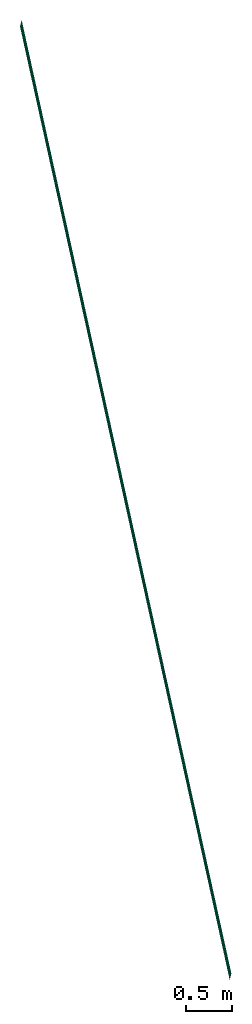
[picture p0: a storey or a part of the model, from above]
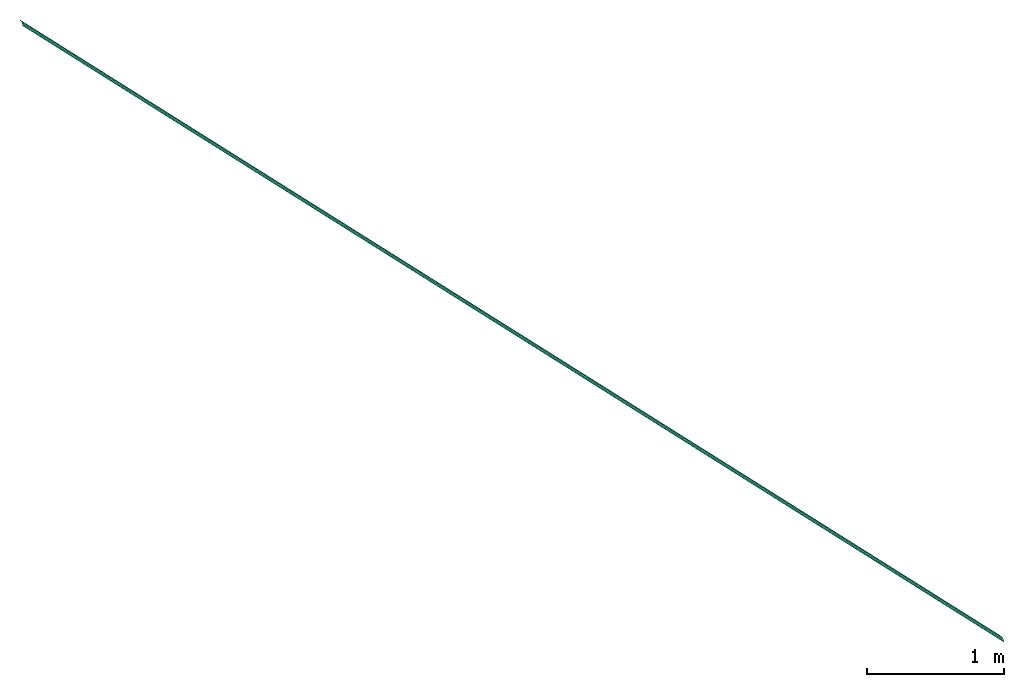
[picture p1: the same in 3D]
Properties of the parts of a building model (IFC2X3), part 1 of 2

# File
Description: ViewDefinition [CoordinationView_V2.0, QuantityTakeOffAddOnView]
File name: zv001-a-200-1-0003.ifc (Edited by Naviate Simple BIM 2022 version 6)
Time: 2026-01-09T13:08:05+01:00
Written by: ODA SDAI 24.12
Made in: Autodesk Revit 25.4.30.30 (ENU) - IFC 25.4.0.27

# IfcProject, 10001574
LongName: ENZV Kommersielt areal innland (KAI); Phase: Hovedprosjekt: 01.12.2018

# IfcSite (5)
RefElevation: 0 mm
Name | RefLatitude | RefLongitude
ENZV | 59, 54, 57, 601318 | 10, 44, 59, 999999 | Identity Data - Inventarnr.: ZV001; Building Name: ZV001; CQIncludeDoorSwing: no; CQIncludeRoomNumber: no; CQIncludeRoomNumberWindows: no; CQIncludeWindowSwing: no; Workset: Project Info; Organization Description: BIM 360://Avinor - Stavanger lufthavn/ENZV_ARK_bygg A.rvt; Prosjekt: Stavanger lufthavn, Sola; Text - 02_IfcSite: STAVANGER LUFTHAVN; 01_Modellfil: zv001-a-200-1-0003.rvt; Prosjektleder: Livar Husveg; Tiltaket gjelder: Kommersielt areal innland, KAI; Other - Project Number: 10001574; CQDoorSwingCodes: Left=V;Right=H;notMirrored =L;mirrored =R; Project Issue Date: Tilbudsprosjekt: 22.07.2018; CQWindowSwingCodes: Left=Rettv.;Right=Speilv.; Category: Project Information; Project Address: Enter address here; CQPhaseFilter: Existing:True;New Construction:True;Fase 2.0:True;Fase 3.0:True;Fase 3.9:True;Fase 4.0:True;Fase 5.1:True;Fase 5.2:True;Fase 5.3:True;Fase 5.4:True;Fase 5.9:True;Fase 5.10:True;Fase plot tegninger:True;Fase 6.0:True;; CQIncludeTemporaryDoors: no; Project Name: ENZV Kommersielt areal innland (KAI); Project Status: Hovedprosjekt: 01.12.2018; Tiltakshavers navn: Livar Husveg
Default | 42, 24, 53, 508911 | -71, -15, -29, -58837 | Pset_ProductRequirements - Category: Project Information
2 x ENZV | 58, 58, 11, 908264 | 5, 43, 59, 185523
 | 58, 58, 11, 908264 | 5, 43, 59, 185523

# IfcBuilding (5)
Name
ZV001 | LongName: ZV001; Pset_BuildingCommon - NumberOfStoreys: 8; Identity Data - Inventarnr.: ZV001; Building Name: ZV001; CQIncludeDoorSwing: no; CQIncludeRoomNumber: no; CQIncludeRoomNumberWindows: no; CQIncludeWindowSwing: no; Workset: Project Info; Organization Description: BIM 360://Avinor - Stavanger lufthavn/ENZV_ARK_bygg A.rvt; Prosjekt: Stavanger lufthavn, Sola; Text - 02_IfcSite: STAVANGER LUFTHAVN; 01_Modellfil: zv001-a-200-1-0003.rvt; Prosjektleder: Livar Husveg; Tiltaket gjelder: Kommersielt areal innland, KAI; Other - Project Number: 10001574; CQDoorSwingCodes: Left=V;Right=H;notMirrored =L;mirrored =R; Project Issue Date: Tilbudsprosjekt: 22.07.2018; CQWindowSwingCodes: Left=Rettv.;Right=Speilv.; Category: Project Information; Project Address: Enter address here; CQPhaseFilter: Existing:True;New Construction:True;Fase 2.0:True;Fase 3.0:True;Fase 3.9:True;Fase 4.0:True;Fase 5.1:True;Fase 5.2:True;Fase 5.3:True;Fase 5.4:True;Fase 5.9:True;Fase 5.10:True;Fase plot tegninger:True;Fase 6.0:True;; CQIncludeTemporaryDoors: no; Project Name: ENZV Kommersielt areal innland (KAI); Project Status: Hovedprosjekt: 01.12.2018; Tiltakshavers navn: Livar Husveg
 | Pset_BuildingCommon - NumberOfStoreys: 4; Pset_ProductRequirements - Category: Project Information
2 x ZV001
mc-building

# IfcBuildingStorey (3)
Name | In | Elevation (mm)
H01 | ZV001 | 5100
Nullnivå | ZV001 | 0
Plan 01 | mc-building | 5100

# IfcBuildingStorey: Level:8mm Nivåhode Lokale Koter (2)
In: ZV001
Identity Data - Structural: no; Building Story: yes; Workset: Shared Levels and Grids
Graphics(Type) - Line Pattern: Centre; Color: 0; Symbol at End 1 Default: no; Symbol at End 2 Default: yes; Line Weight: 1; Symbol: View - Nivåhode1 : Nivåhode Trekant 2
Identity Data(Type) - Workset: Level Types; Type Name: 8mm Nivåhode Lokale Koter
Constraints(Type) - Elevation Base: Project Base Point
Other - Type Id: 305; Category: Levels; Family and Type: Level: 8mm Nivåhode Lokale Koter; Family: Level; Type: 8mm Nivåhode Lokale Koter
Pset_AirSideSystemInformation - sets with these values: 2
Other(Type) - Category: Levels; Family Name: Level
Phasing - Fagkode: ARK
Name | LongName = Identity Data, Name = Pset_AirSideSystemInformation, Name = Etasjekoder | Elevation (mm) = Constraints, Elevation (mm) | Computation Height (mm)
H01 | H01 | 5100 | 1200
H02 | H02 | 9300 | 0

# IfcBuildingStorey: Level:NO_Nivå_meter-Project, PLAN 01. ETG
LongName: PLAN 01. ETG; Elevation: 5100 mm
Pset_AirSideSystemInformation - Name: PLAN 01. ETG
Pset_ProductRequirements - Name: PLAN 01. ETG; Category: Levels

# IfcBuildingStorey: Level:NO_Nivå_meter-Shared (2)
Pset_ProductRequirements - Category: Levels
Name | LongName | Elevation (mm) | Pset_AirSideSystemInformation, Name = Pset_ProductRequirements, Name
PLAN 0. ETG | PLAN 0. ETG | 2100 | 0-nivå
PLAN 02. ETG | PLAN 02. ETG | 9300 | PLAN 02. ETG

# IfcAnnotation, Model Lines:3044847
In: H01
ePset_LocationTool - Splitting: ORIGINAL
ePset_Simplebim - Assembly Level: Leaf
Group: Model Group:Group 14:3044862

# IfcBeam: NO_S-Frame_Steel_RHS (EN 10219-2_Cold formed welded):CF-RHS120x60x5, NO_S-Frame_Steel_RHS (EN 10219-2_Cold formed welded):CF-RHS120x60x5:998443
In: PLAN 02. ETG
Type - Pset_BeamCommon - IsExternal: no; LoadBearing: yes; Reference: CF-RHS120x60x5
Type - Pset_ProductRequirements - Category: Structural Framing
Type - Pset_QuantityTakeOff - Reference: CF-RHS120x60x5
Type - Pset_ReinforcementBarPitchOfBeam - Reference: CF-RHS120x60x5
Pset_QuantityTakeOff - sets with these values: 2
ePset_LocationTool - Splitting: RESULT
ePset_Simplebim - Assembly Level: Leaf
ePset_SimplebimBasicQuantities - Area, sides, net (Simplebim): 1.24379 m2; Weight, as steel (Simplebim): 24.2932 kg; Width (Simplebim): 60 mm; Height (Simplebim): 120 mm; Length (Simplebim): 1952 mm; Volume, net (Simplebim): 0.00309468 m3

# IfcBuildingElementProxy: Stålplate for innfesting av sekundærstål:70x10x80 (2)
In: PLAN 0. ETG
Type - Material: NO_Metall - Stål - S355
Type - Pset_BuildingElementProxyCommon - Reference: 70x10x80
Type - Pset_ProductRequirements - Category: Generic Models
Type - Pset_QuantityTakeOff - Reference: 70x10x80
Type - Pset_ProvisionForVoid - Height: 70 mm
ePset_SimplebimBasicQuantities - Area, largest surface, net (Simplebim): 0.0056 m2; Thickness (Simplebim): 10 mm; Length (Simplebim): 80 mm; Height (Simplebim): 70 mm; Volume, net (Simplebim): 0.000056 m3
ePset_LocationTool - Splitting: ORIGINAL
Pset_BuildingElementProxyCommon - sets with these values: 2
ePset_Simplebim - Assembly Level: Leaf
Name (Stålplate for innfesting av sekundærstål:70x10x80:...)
1064360
1064416

# IfcColumn: NO_S-Column_Precast_Round:Pullert ø350 (4)
In: PLAN 01. ETG
Type - PredefinedType: COLUMN; Material: NO_Betong - Prefab
Type - Pset_ColumnCommon - Reference: Pullert ø350; IsExternal: no; LoadBearing: yes
Type - Pset_ProductRequirements - Category: Structural Columns
Type - Pset_QuantityTakeOff - Reference: Pullert ø350
Type - Pset_ReinforcementBarPitchOfColumn - Reference: Pullert ø350
ePset_LocationTool - Splitting: ORIGINAL
Pset_ReinforcementBarPitchOfColumn - sets with these values: 2
ePset_SimplebimBasicQuantities - Width (Simplebim): 350 mm; Depth (Simplebim): 350 mm; Volume, net (Simplebim): 0.129227 m3; Area, sides, net (Simplebim): 1.48252 m2; Weight, as steel (Simplebim): 1014.43 kg; Height (Simplebim): 1350 mm
AVINOR - 03_Ansvar: RIB Norconsult; 06_Omrade: ZV000; 05_ID-nummer: +ZV000=725.0015-QM0002; 01_Lufthavnkode: ENZV; 02_Prosjekt: 10002213
ePset_Simplebim - Assembly Level: Leaf
Name (NO_S-Column_Precast_Round:Pullert ø350:...)
881852
920528
920607
921051

# IfcColumn: Søyle Betong Sirkulær:350 (3)
In: H01
Type - PredefinedType: COLUMN; Material: Betong Plasstøpt - B35
Type - Other - Category: Structural Columns; Family Name: Søyle Betong Sirkulær; k1: 3.14159
Type - Dimensions - D: 350 mm; Perimeter: 1099.56 mm
Type - Identity Data - Type Name: 350; URL: www.cad-q.no; Workset: Family : Structural Columns : Søyle Betong Sirkulær
Type - Structural - Section Shape: 0
Type - Pset_ColumnCommon - LoadBearing: yes
Phasing - Phase Created: Fase 1 - Som bygget
ePset_LocationTool - Splitting: RESULT
Pset_QuantityTakeOff - Reference: 350; sets with these values: 2
Pset_ColumnCommon - IsExternal: no; Reference: 350
Identity Data - Has Association: yes; Workset: Workset1
Other - Family and Type: Søyle Betong Sirkulær: 350; Type Id: 414188; Family: Søyle Betong Sirkulær; Type: 350
Constraints - Room Bounding: no; Moves With Grids: no; Level: H01; Base Level: H01; Top Level: H02; Column Style: Vertical
Structural - Rebar Cover - Top Face: Rebar Cover 1 <25 mm>; Rebar Cover - Other Faces: Rebar Cover 1 <25 mm>; Rebar Cover - Bottom Face: Rebar Cover 1 <25 mm>
ePset_SimplebimBasicQuantities - Volume, net (Simplebim): 0.335032 m3; Area, sides, net (Simplebim): 3.84357 m2; Weight, as steel (Simplebim): 2630 kg; Width (Simplebim): 350 mm; Depth (Simplebim): 350 mm; Height (Simplebim): 3500 mm
ePset_Simplebim - Assembly Level: Leaf
Materials and Finishes - Structural Material: Betong Plasstøpt - B35
Name (Søyle Betong Sirkulær:350:...) | Column Location Mark
3049581 | P1-CM03
3049587 | P1-CM04
3049605 | P1-CM05

# IfcCovering: Compound Ceiling:ENZV_H01_Perf gipshimling 600x600mm (9)
Type - PredefinedType: CEILING
Type - Other - Category: Ceilings; Family Name: Compound Ceiling
Type - Construction - Thickness: 80 mm
Type - Graphics - Coarse Scale Fill Color: 0
Type - Identity Data - Type Mark: H-03; Type Name: ENZV_H01_Perf gipshimling 600x600mm; Workset: Ceiling Types
Type - Analytical Properties - Absorptance: 0.1; Roughness: 1
Type - Pset_CoveringCommon - TotalThickness: 80 mm
ePset_SimplebimBasicQuantities - Height (Simplebim): 80 mm
Phasing - Phase Created: Fase 1 - Som bygget
Pset_CoveringCommon - Reference: ENZV_H01_Perf gipshimling 600x600mm; Finish: Systemhimling 600x600mm;
Other - Type: ENZV_H01_Perf gipshimling 600x600mm; Type Id: 389168; Family: Compound Ceiling; Family and Type: Compound Ceiling: ENZV_H01_Perf gipshimling 600x600mm
ePset_Simplebim - Assembly Level: Leaf
Constraints - Room Bounding: yes
Pset_QuantityTakeOff - Reference: ENZV_H01_Perf gipshimling 600x600mm
Identity Data - Workset: Workset1
Name (Compound Ceiling:ENZV_H01_Perf gipshimling 600x600mm:...) | In | Length (Simplebim) (mm) | Area, largest surface, net (Simplebim) (m2) | Volume, net (Simplebim) (m3) | Width (Simplebim) (mm) | Splitting | Level
3048940 | H01 | 24891.2 | 40.489 | 4.44493 | 15432.8 | ORIGINAL | H01 | Material: Standard 64 mm, Systemhimling 600x600mm 16 mm; Dimensions - Area: 55.5616 m2; Volume: 4.44493 m3; Perimeter: 66600.8 mm; Constraints - Height Offset From Level: 2700 mm; BaseQuantities - GrossCeilingArea: 55.5616 m2
3023942 | H02 | 23126 | 47.0245 | 3.762 | 14410 | RESULT | H02
3049153 | H02 | 5021 | 8.6928 | 0.695426 | 3958 | RESULT | H02
3027741 | H01 | 1189 | 0.407996 | 0.0326402 | 1029 | RESULT | H01
3045093 | H01 | 2758 | 3.27832 | 0.262266 | 2249 | RESULT | H01
3026211 | H01 | 4383 | 0.404815 | 0.0000944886 | 2530 | RESULT | H01
3030676 | H01 | 1551 | 0.143186 | 0.0000498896 | 895 | RESULT | H01
3045673 | H01 | 2642 | 1.04163 | 0.0833287 | 2414 | RESULT | H01
3046755 | H01 | 1524 | 0.687985 | 0.0550388 | 1336 | RESULT | H01

# IfcCovering: Compound Ceiling:ENZV_H03_Hygienehimling 600x600mm (2)
In: H01
Type - PredefinedType: CEILING
Type - Other - Category: Ceilings; Family Name: Compound Ceiling
Type - Construction - Thickness: 52 mm
Type - Graphics - Coarse Scale Fill Color: 0
Type - Identity Data - Type Mark: H-03; Type Name: ENZV_H03_Hygienehimling 600x600mm; Workset: Ceiling Types
Type - Analytical Properties - Absorptance: 0.1; Roughness: 1
Type - Pset_CoveringCommon - TotalThickness: 52 mm
Other - Family: Compound Ceiling; Family and Type: Compound Ceiling: ENZV_H03_Hygienehimling 600x600mm; Type Id: 389169; Type: ENZV_H03_Hygienehimling 600x600mm
Phasing - Phase Created: Fase 1 - Som bygget
ePset_SimplebimBasicQuantities - Height (Simplebim): 52 mm
Pset_CoveringCommon - Finish: Systemhimling 600x600mm;; Reference: ENZV_H03_Hygienehimling 600x600mm
Pset_QuantityTakeOff - Reference: ENZV_H03_Hygienehimling 600x600mm
ePset_Simplebim - Assembly Level: Leaf
Constraints - Room Bounding: yes; Level: H01
Identity Data - Workset: Workset1
Name (Compound Ceiling:ENZV_H03_Hygienehimling 600x600mm:...) | Width (Simplebim) (mm) | Volume, net (Simplebim) (m3) | Length (Simplebim) (mm) | Area, largest surface, net (Simplebim) (m2) | Splitting
3049013 | 4722.38 | 0.649877 | 6353.01 | 12.4976 | ORIGINAL | Material: Standard 36 mm, Systemhimling 600x600mm 16 mm; Dimensions - Perimeter: 16215.5 mm; Area: 12.4976 m2; Volume: 0.649877 m3; Constraints - Height Offset From Level: 2800 mm; BaseQuantities - GrossCeilingArea: 12.4976 m2
3026220 | 2258 | 0.0000162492 | 3910 | 0.234781 | RESULT

# IfcCovering: Compound Ceiling:ENZV_H04_Gipsplate 13mm (4)
In: H01
Type - PredefinedType: CEILING
Type - Other - Category: Ceilings; Family Name: Compound Ceiling
Type - Construction - Thickness: 13 mm
Type - Graphics - Coarse Scale Fill Color: 16777215; Coarse Scale Fill Pattern: Vinyl transparent
Type - Identity Data - Type Mark: H-04; Type Name: ENZV_H04_Gipsplate 13mm; Workset: Ceiling Types
Type - Analytical Properties - Absorptance: 0.1; Roughness: 1
Type - Pset_CoveringCommon - TotalThickness: 13 mm
Phasing - Phase Created: Fase 1 - Som bygget
ePset_SimplebimBasicQuantities - Height (Simplebim): 13 mm
ePset_Simplebim - Assembly Level: Leaf
Pset_CoveringCommon - Reference: ENZV_H04_Gipsplate 13mm; sets with these values: 2
Other - Family: Compound Ceiling; Type Id: 2906492; Type: ENZV_H04_Gipsplate 13mm; Family and Type: Compound Ceiling: ENZV_H04_Gipsplate 13mm
Constraints - Room Bounding: yes; Level: H01
Identity Data - Workset: Workset1
Name (Compound Ceiling:ENZV_H04_Gipsplate 13mm:...) | Splitting | Width (Simplebim) (mm) | Area, largest surface, net (Simplebim) (m2) | Volume, net (Simplebim) (m3) | Length (Simplebim) (mm)
3049000 | ORIGINAL | 14582.8 | 16.9692 | 0.220599 | 24958.2 | Material: Gips 13 mm; Dimensions - Volume: 0.220599 m3; Area: 16.9691 m2; Perimeter: 57891.9 mm; Constraints - Height Offset From Level: 2700 mm; BaseQuantities - GrossCeilingArea: 16.9691 m2
3027614 | RESULT | 862 | 0.514923 | 0.00669397 | 1194
3049255 | RESULT | 1361 | 0.768699 | 0.0099932 | 1429
3026193 | RESULT | 1363 | 0.0354253 | 0.0000167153 | 2360

# IfcCovering: Compound Ceiling:Systemhimling 600x600mm (5)
Type - PredefinedType: CEILING
Type - Other - Category: Ceilings; Family Name: Compound Ceiling
Type - Construction - Thickness: 52 mm
Type - Graphics - Coarse Scale Fill Color: 0
Type - Identity Data - Type Name: Systemhimling 600x600mm; Workset: Ceiling Types
Type - Analytical Properties - Absorptance: 0.1; Roughness: 1
Type - Pset_CoveringCommon - TotalThickness: 52 mm
Phasing - Phase Created: Fase 1 - Som bygget
Pset_QuantityTakeOff - Reference: Systemhimling 600x600mm
Other - Type: Systemhimling 600x600mm; Family: Compound Ceiling; Family and Type: Compound Ceiling: Systemhimling 600x600mm; Type Id: 2906167
ePset_Simplebim - Assembly Level: Leaf
Pset_CoveringCommon - Reference: Systemhimling 600x600mm; Finish: Systemhimling 600x600mm;
Constraints - Room Bounding: yes
ePset_SimplebimBasicQuantities - Height (Simplebim): 52 mm
Identity Data - Workset: Workset1
Name (Compound Ceiling:Systemhimling 600x600mm:...) | In | Splitting | Level | Length (Simplebim) (mm) | Area, largest surface, net (Simplebim) (m2) | Volume, net (Simplebim) (m3) | Width (Simplebim) (mm)
3049021 | H01 | ORIGINAL | H01 | 18628.3 | 41.4178 | 2.15372 | 11931.2 | Material: Standard 36 mm, Systemhimling 600x600mm 16 mm; Dimensions - Perimeter: 44742.7 mm; Volume: 2.15372 m3; Area: 41.4177 m2; Constraints - Height Offset From Level: 2700 mm; BaseQuantities - GrossCeilingArea: 41.4177 m2
3049569 | H01 | ORIGINAL | H01 | 2389.15 | 2.54646 | 0.132416 | 2101.26 | Material: Standard 36 mm, Systemhimling 600x600mm 16 mm; Dimensions - Perimeter: 6574.35 mm; Volume: 0.132416 m3; Area: 2.54647 m2; Constraints - Height Offset From Level: 2400 mm; BaseQuantities - GrossCeilingArea: 2.54647 m2
3026138 | H01 | RESULT | H01 | 4785 | 8.04887 | 0.418542 | 3798
3026165 | H02 | RESULT | H02 | 2790 | 3.9241 | 0.204053 | 2647
3026176 | H01 | RESULT | H01 | 2758 | 3.64872 | 0.189734 | 2530

# IfcCurtainWall: Curtain Wall:Trespiler, Curtain Wall:Trespiler:3022099
In: H01
Type - Other - Category: Walls; Family Name: Curtain Wall
Type - Construction - Function: Exterior; Automatically Embed: yes; Join Condition: Not Defined
Type - Identity Data - Type Name: Trespiler; Workset: Curtain Wall Types
Type - Horizontal Grid - Adjust for Mullion Size: no
Type - Vertical Grid - Adjust for Mullion Size: yes; Layout: Fixed Distance; Spacing: 300 mm
Type - Vertical Mullions - Interior Type: Rectangular Mullion : 21x45 tre
Analysis Results - CQWallGrossArea: 22.811 m2
Cross-Section Definition - Cross-Section: Vertical
Pset_CurtainWallCommon - Reference: Trespiler; IsExternal: yes
Pset_QuantityTakeOff - Reference: Trespiler
ePset_SimplebimBasicQuantities - Width: 2873.82 mm; Length: 4950.09 mm; Height: 4000 mm; Volume, net (Simplebim): 0.28663 m3
Structural - Structural Usage: Non-bearing; Structural: no
Identity Data - Workset: Workset1
Constraints - Unconnected Height: 4000 mm; Base is Attached: no; Related to Mass: no; Room Bounding: yes; Top Offset: 0 mm; Base Offset: 0 mm; Top is Attached: no; Base Constraint: H01
ePset_Simplebim - Assembly Level: Topmost
Phasing - Phase Created: Fase 1 - Som bygget
Dimensions - Length: 5702.75 mm; Area: 22.811 m2
Horizontal Grid - Number: 4; Angle: 0 deg; Offset: 0 mm; Justification: Beginning
Vertical Grid - Number: 19; Angle: 0 deg; Offset: 0 mm; Justification: Beginning
Other - Type: Trespiler; Family and Type: Curtain Wall: Trespiler; Type Id: 2906376; Family: Curtain Wall
BaseQuantities - Height: 4000 mm; Width: 25 mm; GrossSideArea: 22.811 m2

# IfcDoor: A244-Enfløyet1:DT03B_Tredør 11x21M, A244-Enfløyet1:DT03B_Tredør 11x21M:3048927
In: H01
Type - OperationType: SINGLE_SWING_LEFT; ConstructionType: USERDEFINED; ParameterTakesPrecedence: no; Sizeable: no; Material: Rustfritt Stål, Høytrykkslaminat, Tre
Type - IfcDoorPanelProperties - PanelOperation: SWINGING
Type - Other - Category: Doors; Family Name: A244-Enfløyet1; Karmfalsbredde: 30 mm; M_Height: 21; M_Width: 11
Type - Constraints - CQOriginalSwingDirection: Left
Type - Construction - Construction Type: TD Tredør; Dørblad i plan: no; Dørklinke: Dørklinke - Enkel : Rustfritt; Function: Interior; Terskel: no; Terskeltype: Terskeltype; Wall Closure: By host
Type - Dimensions - Karmbredde: 42 mm; Karmdybde: 100 mm; Karmprofil: 12 mm; Rough Height: 2090 mm; Rough Width: 1090 mm; Thickness: 40 mm
Type - Identity Data - DoorBasalOpening: V; Fire Rating: -; Type Mark: DT03B; Type Name: DT03B_Tredør 11x21M; URL: www.cad-q.no; Workset: Family : Doors : A244-Enfløyet1; CQSwingCount: 12H/13V; CQTypeCount: 25; Description: Kompaktdør med laminatoverflate
Type - Materials and Finishes - Dørbladmateriale: Høytrykkslaminat; Karmmateriale: Tre; Terskelmateriale: Uten terskel
Type - Analytical Properties - Analytic Construction: <None>; Define Thermal Properties by: Schematic Type
Type - Pset_ConcreteElementGeneral - FireRating: -; ConstructionType: TD Tredør
Type - Pset_DoorCommon - FireRating: -
Type - Text - Kantlist: Eik; Karm S: Tre
OverallHeight: 2110 mm; OverallWidth: 1110 mm
Dimensions - Spalte Side: 10 mm; Spalte Topp: 20 mm; Innsetting Dør: 20 mm; Veggtykkelse: 145 mm; Width: 1110 mm; Height: 2110 mm; Volume: 0.10026 m3; Area: 3.05879 m2
ePset_LocationTool - Splitting: ORIGINAL
Phasing - Phase Created: Fase 1 - Som bygget
Text - Terskel: Uten terskel; Fargekode: NCS S4500-N; Kortleser: X; Låskasse: X; Vrider: X; Sylinder: El sluttstykke
Pset_QuantityTakeOff - Reference: DT03B_Tredør 11x21M
Constraints - Sill Height: 0 mm; Level: H01
Other - Family: A244-Enfløyet1; Type Id: 2906908; Family and Type: A244-Enfløyet1: DT03B_Tredør 11x21M; Sparkeplate: Begge sider, h 900mm; Type: DT03B_Tredør 11x21M; Host Id: 3048924; Dørpumpe: X; Innsetoffset: 1020 mm; Head Height: 2110 mm
ePset_SimplebimBasicQuantities - Area, opening (Simplebim): 2.3421 m2; Length, frame (Simplebim): 5270 mm; Height (Simplebim): 2090 mm; Height, opening (Simplebim): 2110 mm; Width, opening (Simplebim): 1110 mm; Area (Simplebim): 2.2781 m2; Width (Simplebim): 1090 mm
ePset_Simplebim - Assembly Level: Leaf
Identity Data - Mark: B1028.02; CQSwingDirection: H; 08_Brannkrav: -; Workset: Workset1
Pset_DoorCommon - IsExternal: no; Reference: DT03B_Tredør 11x21M
AVINOR - 08_Brannkrav: -
BaseQuantities - Area: 2.3421 m2; Width: 1110 mm; Height: 2110 mm

# IfcDoor: A244-Enfløyet1:Tredør 10x21M, A244-Enfløyet1:Tredør 10x21M:3043777
In: H01
Type - OperationType: SINGLE_SWING_LEFT; ConstructionType: USERDEFINED; ParameterTakesPrecedence: no; Sizeable: no; Material: Rustfritt Stål, Hvit
Type - IfcDoorPanelProperties - PanelOperation: SWINGING
Type - Other - Category: Doors; Family Name: A244-Enfløyet1; Karmfalsbredde: 30 mm; M_Height: 21; M_Width: 10
Type - Constraints - CQOriginalSwingDirection: Left
Type - Construction - Construction Type: TD Tredør; Dørblad i plan: no; Dørklinke: Dørklinke - Enkel : Rustfritt; Function: Interior; Terskel: no; Terskeltype: Terskeltype; Wall Closure: By host
Type - Dimensions - Karmbredde: 42 mm; Karmdybde: 100 mm; Karmprofil: 12 mm; Rough Height: 2090 mm; Rough Width: 990 mm; Thickness: 40 mm
Type - Identity Data - DoorBasalOpening: V; Fire Rating: -; Type Mark: D - 10x21VVV; Type Name: Tredør 10x21M; URL: www.cad-q.no; Workset: Family : Doors : A244-Enfløyet1; CQSwingCount: 25H/24V; CQTypeCount: 49
Type - Materials and Finishes - Dørbladmateriale: Hvit; Karmmateriale: Hvit; Terskelmateriale: Tre
Type - Analytical Properties - Analytic Construction: <None>; Define Thermal Properties by: Schematic Type
Type - Pset_ConcreteElementGeneral - FireRating: -; ConstructionType: TD Tredør
Type - Pset_DoorCommon - FireRating: -
OverallHeight: 2110 mm; OverallWidth: 1010 mm
Pset_QuantityTakeOff - Reference: Tredør 10x21M
Phasing - Phase Created: Fase 1 - Som bygget
Other - Host Id: 3046713; Family and Type: A244-Enfløyet1: Tredør 10x21M; Family: A244-Enfløyet1; Type Id: 984171; Type: Tredør 10x21M; Innsetoffset: 950 mm; Head Height: 2110 mm
Dimensions - Innsetting Dør: -50 mm; Volume: 0.09176 m3; Spalte Side: 10 mm; Spalte Topp: 20 mm; Veggtykkelse: 120 mm; Width: 1010 mm; Height: 2110 mm; Area: 2.82579 m2
Pset_DoorCommon - IsExternal: no; Reference: Tredør 10x21M
ePset_LocationTool - Splitting: ORIGINAL
Constraints - Sill Height: 0 mm; Level: H01
ePset_SimplebimBasicQuantities - Length, frame (Simplebim): 5170 mm; Height (Simplebim): 2090 mm; Height, opening (Simplebim): 2110 mm; Width, opening (Simplebim): 1010 mm; Area (Simplebim): 2.0691 m2; Width (Simplebim): 990 mm; Area, opening (Simplebim): 2.1311 m2
ePset_Simplebim - Assembly Level: Leaf
Identity Data - Mark: C1016.1; 08_Brannkrav: -; Workset: Workset1
AVINOR - 08_Brannkrav: -
BaseQuantities - Width: 1010 mm; Height: 2110 mm; Area: 2.1311 m2

# IfcElectricalCircuit (2)
Description: 443
Name
Nødlys
Nødlysutstyr

# IfcFlowSegment: PE 80 trykkrør SDR 11
In: Nullnivå
Type - Description: PE 80 trykkrør SDR 11; PredefinedType: RIGIDSEGMENT
ePset_SimplebimBasicQuantities - Height (Simplebim): 16 mm; Width (Simplebim): 33 mm; Length (Simplebim): 10686 mm
ePset_Simplebim - Assembly Level: Leaf
ePset_LocationTool - Splitting: RESULT
Group: 31= KV 4 (6)

# IfcFlowTerminal: JumboLED II Enkeltsidig PO/BL
In: Plan 01
Type - Description: Armatuur met vluchtwegaanduiding voor plafondmontage
ePset_LocationTool - Splitting: ORIGINAL
ePset_Simplebim - Assembly Level: Leaf
Pset_ElectricalDeviceCommon - NominalVoltage: 0; ElectricalDeviceNominalPower: 0 W; NumberOfPoles: 0
Pset_LightFixtureTypeCommon - TotalWattage: 0 W
Group: Nødlysutstyr

# IfcFlowTerminal: SP-15-K80-68DGR-STD
In: H01
Type - Description: Sprinklerhode i Himling, STD, K=80
ePset_LocationTool - Splitting: ORIGINAL
ePset_Simplebim - Assembly Level: Leaf
Group: 330.002 Ankomst

# IfcFlowTerminal: Schneider Outdoor Wall IP65
In: Plan 01
Type - Description: Schneider Outdoor Wall IP65
ePset_LocationTool - Splitting: ORIGINAL
Pset_ElectricalDeviceCommon - NumberOfPoles: 1; ElectricalDeviceNominalPower: 0.6 W; IP_Code: 65; NominalVoltage: 230
ePset_Simplebim - Assembly Level: Leaf
Pset_LightFixtureTypeCommon - TotalWattage: 0.6 W
Group: Nødlys

# IfcGroup: Model Group:Group 14, Model Group:Group 14:3044862
Identity Data(Type) - Type Name: Group 14; Workset: Workset1
Identity Data - Workset: Workset1
Constraints - Origin Level Offset: 0 mm; Reference Level: H01
Other(Type) - Category: Model Groups; Family Name: Model Group
Other - Category: Model Groups; Family and Type: Model Group: Group 14; Family: Model Group; Type: Group 14; Type Id: 2896871

# IfcMember: Rectangular Mullion:21x45 tre (19)
In: H01
Type - PredefinedType: MULLION; Material: Eik
Type - Other - Category: Curtain Wall Mullions; Family Name: Rectangular Mullion
Type - Constraints - Angle: 0 deg; Offset: 0 mm
Type - Construction - Corner Mullion: no; Position: Perpendicular to Face; Profile: System Mullion Profile: Rectangular; Thickness: 45 mm
Type - Dimensions - Width on side 1: 11 mm; Width on side 2: 11 mm
Type - Identity Data - Type Name: 21x45 tre; Workset: Family : Curtain Wall Mullions : Rectangular Mullion
Type - Materials and Finishes - Material: Eik
ePset_LocationTool - Splitting: RESULT
Pset_MemberCommon - IsExternal: yes; Reference: 21x45 tre
Identity Data - Workset: Workset1
Other - Family: Rectangular Mullion; Host Id: 3022099; Type Id: 2906378; Family and Type: Rectangular Mullion: 21x45 tre; Type: 21x45 tre
Constraints - Level: H01
Pset_QuantityTakeOff - Reference: 21x45 tre
ePset_Simplebim - Assembly Level: Leaf
Phasing - Phase Created: Fase 1 - Som bygget
ePset_SimplebimBasicQuantities - Volume, net (Simplebim): 0.003465 m3; Weight, as steel (Simplebim): 27.2003 kg; Width (Simplebim): 22 mm; Length (Simplebim): 44 mm; Height (Simplebim): 3500 mm; Area, sides, net (Simplebim): 0.47098 m2
Name (Rectangular Mullion:21x45 tre:...)
3022121
3022122
3022123
3022124
3022125
3022126
3022127
3022128
3022129
3022130
3022133
3022150
3022151
3022152
3022153
3022154
3022155
3022156
3022157

# IfcPlate: System Panel:Glassfelt 10mm (20)
In: H01
Type - PredefinedType: CURTAIN_PANEL; Material: Glass
Type - Other - Category: Curtain Panels; Family Name: System Panel
Type - Constraints - Offset: 0 mm
Type - Dimensions - Thickness: 10 mm
Type - Identity Data - Type Name: Glassfelt 10mm; Workset: Family : Curtain Panels : System Panel
Type - Materials and Finishes - Material: Glass
Type - Analytical Properties - Define Thermal Properties by: Schematic Type; Analytic Construction: <None>
Pset_QuantityTakeOff - Reference: Glassfelt 10mm
Pset_PlateCommon - Reference: Glassfelt 10mm; IsExternal: yes
Identity Data - Workset: Workset1
Constraints - Level: H01
ePset_LocationTool - Splitting: RESULT
Phasing - Phase Created: Fase 1 - Som bygget
ePset_Simplebim - Assembly Level: Leaf
Other - Type Id: 128792; Host Id: 3022099; Type: Glassfelt 10mm; Family: System Panel; Family and Type: System Panel: Glassfelt 10mm
Name (System Panel:Glassfelt 10mm:...) | Area, largest surface, net (Simplebim) (m2) | Volume, net (Simplebim) (m3) | Weight, as steel (Simplebim) (kg)
3022100 | 0.973 | 0.00973 | 76.3805
3022102 | 0.973 | 0.00973 | 76.3805
3022104 | 0.973 | 0.00973 | 76.3805
3022106 | 0.973 | 0.00973 | 76.3805
3022108 | 0.973 | 0.00973 | 76.3805
3022110 | 0.973 | 0.00973 | 76.3805
3022112 | 0.973 | 0.00973 | 76.3805
3022114 | 0.973 | 0.00973 | 76.3805
3022116 | 0.973 | 0.00973 | 76.3805
3022118 | 0.973 | 0.00973 | 76.3805
3022120 | 0.973 | 0.00973 | 76.3805
3022132 | 0.973 | 0.00973 | 76.3805
3022135 | 0.973 | 0.00973 | 76.3805
3022137 | 0.973 | 0.00973 | 76.3805
3022139 | 0.973 | 0.00973 | 76.3805
3022141 | 0.973 | 0.00973 | 76.3805
3022143 | 0.973 | 0.00973 | 76.3805
3022145 | 0.973 | 0.00973 | 76.3805
3022147 | 0.973 | 0.00973 | 76.3805
3022149 | 0.035 | 0.0000962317 | 0.755419

# IfcSlab: Floor:ENZV_G01_Banebelegg linoleum (5)
In: H01
Type - PredefinedType: FLOOR; Material: Gulv - Linoleum 2.5 mm, Avretting 12.5 mm
Type - Other - Category: Floors; Family Name: Floor
Type - Construction - Function: Interior; Default Thickness: 15 mm
Type - Graphics - Coarse Scale Fill Color: 6974058; Coarse Scale Fill Pattern: Linoleum
Type - Identity Data - Type Name: ENZV_G01_Banebelegg linoleum; Workset: Floor Types; Type Mark: G01
Type - Analytical Properties - Absorptance: 0.1; Roughness: 1
Type - Materials and Finishes - Structural Material: Avretting
Pset_ReinforcementBarPitchOfSlab - Reference: ENZV_G01_Banebelegg linoleum; sets with these values: 2
Pset_SlabCommon - Reference: ENZV_G01_Banebelegg linoleum; LoadBearing: no; IsExternal: no
ePset_LocationTool - Splitting: RESULT
Identity Data - Has Association: no; Workset: Workset1
Phasing - Phase Created: Fase 1 - Som bygget
ePset_SimplebimBasicQuantities - Thickness (Simplebim): 15 mm
Other - Type Id: 389156; Type: ENZV_G01_Banebelegg linoleum; Family and Type: Floor: ENZV_G01_Banebelegg linoleum; Family: Floor
Constraints - Related to Mass: no; Room Bounding: yes; Level: H01
ePset_Simplebim - Assembly Level: Leaf
Structural - Structural: no
Name (Floor:ENZV_G01_Banebelegg linoleum:...) | Area, sides, net (Simplebim) (m2) | Area, top, net (Simplebim) (m2) | Area, largest surface, net (Simplebim) (m2) | Perimeter (Simplebim) (mm) | Volume, net (Simplebim) (m3)
3042600:2 | 0.0710332 | 0.000394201 | 0.0355137 | 4735.55 | 0.00000591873
3042600:3 | 0.151812 | 0.00202731 | 0.0759 | 10120.8 | 0.0000304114
3042600:4 | 0.053415 | 0.000860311 | 0.0267003 | 3561 | 0.0000129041
3042600:15 | 0.0915122 | 0.00254044 | 0.0457438 | 6100.81 | 0.0000381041
3046775 | 0.0766476 | 1.03632 | 1.03632 | 5109.84 | 0.0155448

# IfcSlab: Floor:ENZV_G03_Banebelegg vinyl (2)
In: H01
Type - PredefinedType: FLOOR; Material: Gulv - Vinyl 2.5 mm, Avretting 12.5 mm
Type - Other - Category: Floors; Family Name: Floor
Type - Construction - Function: Interior; Default Thickness: 15 mm
Type - Graphics - Coarse Scale Fill Color: 6974058; Coarse Scale Fill Pattern: Vinyl
Type - Identity Data - Type Name: ENZV_G03_Banebelegg vinyl; Workset: Floor Types; Type Mark: G03
Type - Analytical Properties - Absorptance: 0.1; Roughness: 1
Type - Materials and Finishes - Structural Material: Avretting
Pset_QuantityTakeOff - Reference: ENZV_G03_Banebelegg vinyl; sets with these values: 2
Pset_SlabCommon - LoadBearing: no; IsExternal: no; Reference: ENZV_G03_Banebelegg vinyl
Identity Data - Has Association: no; Workset: Workset1
Phasing - Phase Created: Fase 1 - Som bygget
ePset_SimplebimBasicQuantities - Thickness (Simplebim): 15 mm
Other - Type Id: 2582780; Family and Type: Floor: ENZV_G03_Banebelegg vinyl; Type: ENZV_G03_Banebelegg vinyl; Family: Floor
Constraints - Related to Mass: no; Room Bounding: yes; Level: H01
ePset_Simplebim - Assembly Level: Leaf
Structural - Structural: no
ePset_LocationTool - Splitting: RESULT
Name (Floor:ENZV_G03_Banebelegg vinyl:...) | Area, top, net (Simplebim) (m2) | Area, sides, net (Simplebim) (m2) | Perimeter (Simplebim) (mm) | Volume, net (Simplebim) (m3) | Area, largest surface, net (Simplebim) (m2)
3036546 | 0.0220748 | 0.135746 | 9049.75 | 0.00033112 | 0.0678
3036546:2 | 0.00146371 | 0.081756 | 5450.4 | 0.0000219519 | 0.0408702

# IfcSlab: Floor:ENZV_G04_Flis mørk grå 15mm (2)
In: H01
Type - PredefinedType: FLOOR; Material: Fliser 600x600mm mørk grå 15 mm
Type - Other - Category: Floors; Family Name: Floor
Type - Construction - Function: Interior; Default Thickness: 15 mm
Type - Graphics - Coarse Scale Fill Color: 0
Type - Identity Data - Type Name: ENZV_G04_Flis mørk grå 15mm; Workset: Floor Types; Type Mark: ENZV_G04
Type - Analytical Properties - Absorptance: 0.1; Roughness: 1
Type - Materials and Finishes - Structural Material: Fliser 600x600mm mørk grå
Pset_QuantityTakeOff - Reference: ENZV_G04_Flis mørk grå 15mm; sets with these values: 2
Pset_SlabCommon - Reference: ENZV_G04_Flis mørk grå 15mm; LoadBearing: no; IsExternal: no
Other - Type Id: 2906451; Type: ENZV_G04_Flis mørk grå 15mm; Family and Type: Floor: ENZV_G04_Flis mørk grå 15mm; Family: Floor
ePset_SimplebimBasicQuantities - Thickness (Simplebim): 15 mm
Identity Data - Has Association: no; Workset: Workset1
ePset_LocationTool - Splitting: RESULT
Phasing - Phase Created: Fase 1 - Som bygget
Constraints - Related to Mass: no; Room Bounding: no; Level: H01
ePset_Simplebim - Assembly Level: Leaf
Structural - Structural: no
Name (Floor:ENZV_G04_Flis mørk grå 15mm:...) | Area, sides, net (Simplebim) (m2) | Area, largest surface, net (Simplebim) (m2) | Area, top, net (Simplebim) (m2) | Perimeter (Simplebim) (mm) | Volume, net (Simplebim) (m3)
3050167 | 0.196481 | 8.52942 | 8.52929 | 13098.8 | 0.12794
3031216 | 0.978444 | 126.338 | 126.339 | 65229.6 | 1.89507

# IfcSlab: Floor:Standard 220mm, Floor:Standard 220mm:3043721
In: H02
Type - PredefinedType: FLOOR; Material: Betong - Plasstøpt 220 mm
Type - Other - Category: Floors; Family Name: Floor
Type - Construction - Function: Interior; Default Thickness: 220 mm
Type - Graphics - Coarse Scale Fill Color: 0
Type - Identity Data - Type Name: Standard 220mm; Workset: Floor Types
Type - Analytical Properties - Absorptance: 0.1; Roughness: 1
Type - Materials and Finishes - Structural Material: Betong - Plasstøpt
ePset_LocationTool - Splitting: RESULT
Other - Family and Type: Floor: Standard 220mm; Type Id: 2906780; Type: Standard 220mm; Family: Floor
ePset_SimplebimBasicQuantities - Volume, net (Simplebim): 0.991164 m3; Area, largest surface, net (Simplebim): 6.54866 m2; Area, sides, net (Simplebim): 13.3064 m2; Area, top, net (Simplebim): 4.50565 m2; Perimeter (Simplebim): 60483.6 mm; Thickness (Simplebim): 220 mm
Identity Data - Has Association: no; Workset: Workset1
Phasing - Phase Created: Fase 1 - Som bygget
Pset_ReinforcementBarPitchOfSlab - Reference: Standard 220mm; sets with these values: 2
Pset_SlabCommon - LoadBearing: no; IsExternal: no; Reference: Standard 220mm
Constraints - Related to Mass: no; Room Bounding: yes; Level: H02
ePset_Simplebim - Assembly Level: Leaf
Structural - Structural: no

# IfcSystem (2)
Name | Description
330.002 Ankomst | 330.002 Ankomst
31= KV 4 (6) | 31= KV 4 (6)

# IfcWall: Basic Wall:ENZV_IV-UK02_S95_145mm_OSBG (2)
In: H01
Type - PredefinedType: STANDARD; Material: A246.Gips 12.5mm fiberarmert -QK5.31112 13 mm, OSB plate 12 mm, A242.Stender Lettmetall 95mm -PJ3.111002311 95 mm, OSB plate 12 mm, A246.Gips 12.5mm fiberarmert -QK5.31112 13 mm
Type - Other - Category: Walls; Family Name: Basic Wall
Type - Construction - Function: Interior; Width: 145 mm; Wrapping at Inserts: Do not wrap; CQMaxWallHeight: 6000 mm
Type - Graphics - Coarse Scale Fill Color: 0
Type - Identity Data - Type Name: ENZV_IV-UK02_S95_145mm_OSBG; Workset: Wall Types; Type Mark: IV-UK02
Type - Analytical Properties - Absorptance: 0.1; Roughness: 1
Type - Materials and Finishes - Structural Material: A242.Stender Lettmetall 95mm -PJ3.111002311
Type - Text - Veggtype S: ENZV_IV-UK02_S95_145mm_OSBG
Phasing - Phase Created: Fase 1 - Som bygget
Pset_QuantityTakeOff - Reference: ENZV_IV-UK02_S95_145mm_OSBG; sets with these values: 2
Cross-Section Definition - Cross-Section: Vertical
Constraints - Location Line: Finish Face: Exterior; Base Extension Distance: 0 mm; Base is Attached: no; Base Offset: 0 mm; Related to Mass: no; Room Bounding: yes; Top Extension Distance: 0 mm; Top is Attached: no; Top Offset: 0 mm; Base Constraint: H01; Unconnected Height: 3676 mm
Structural - Structural Usage: Non-bearing; Structural: no
ePset_LocationTool - Splitting: ORIGINAL
Identity Data - Workset: Workset1
Pset_WallCommon - Reference: ENZV_IV-UK02_S95_145mm_OSBG; IsExternal: no; ExtendToStructure: no; LoadBearing: no
Other - Type Id: 388076; Type: ENZV_IV-UK02_S95_145mm_OSBG; Family: Basic Wall; Family and Type: Basic Wall: ENZV_IV-UK02_S95_145mm_OSBG
ePset_SimplebimBasicQuantities - Thickness (Simplebim): 145 mm; Height (Simplebim): 3676 mm
ePset_Simplebim - Assembly Level: Leaf
BaseQuantities - Width: 145 mm
Name (Basic Wall:ENZV_IV-UK02_S95_145mm_OSBG:...) | Area, side, gross, AABB (Simplebim) (m2) | Area, side, gross, average (Simplebim) (m2) = Area, side, net, average (Simplebim) (m2) | Area, largest surface, net (Simplebim) (m2) = Area, side, gross, larger (Simplebim) (m2) = Area, side, net, larger (Simplebim) (m2) = Area (m2) | Length (Simplebim) (mm) | Volume, net (Simplebim) (m3) = Volume (m3) = NetVolume (m3) | Area, side, net, smaller (Simplebim) (m2) = Area, side, gross, smaller (Simplebim) (m2) | Dimensions, Length (mm) = BaseQuantities, Length (mm)
3048925 | 9.16008 | 8.70462 | 8.70465 | 2491.86 | 1.26217 | 8.70459 | 2601.85
3048926 | 9.69287 | 9.09669 | 9.09671 | 2636.8 | 1.31902 | 9.09667 | 2674.29

# IfcWall: Basic Wall:ENZV_S-UK01B_S70_120mm_OSBG tosidig (5)
In: H01
Type - PredefinedType: STANDARD; Material: A246.Gips 12.5mm fiberarmert -QK5.31112 13 mm, OSB plate 12 mm, A242.Stender Lettmetall 95mm -PJ3.111002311 70 mm, OSB plate 12 mm, A246.Gips 12.5mm fiberarmert -QK5.31112 13 mm
Type - Other - Category: Walls; Family Name: Basic Wall
Type - Construction - Function: Interior; Width: 120 mm; Wrapping at Inserts: Do not wrap; CQMaxWallHeight: 6000 mm
Type - Graphics - Coarse Scale Fill Color: 0
Type - Identity Data - Type Name: ENZV_S-UK01B_S70_120mm_OSBG tosidig; Workset: Wall Types
Type - Analytical Properties - Absorptance: 0.1; Roughness: 1
Type - Materials and Finishes - Structural Material: A242.Stender Lettmetall 95mm -PJ3.111002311
Type - Text - Veggtype S: ENZV_S-K01_S95_145mm_OSBG
Phasing - Phase Created: Fase 1 - Som bygget
Pset_ReinforcementBarPitchOfWall - Reference: ENZV_S-UK01B_S70_120mm_OSBG tosidig; sets with these values: 2
Pset_WallCommon - IsExternal: no; ExtendToStructure: no; LoadBearing: no; Reference: ENZV_S-UK01B_S70_120mm_OSBG tosidig
Other - Family: Basic Wall; Family and Type: Basic Wall: ENZV_S-UK01B_S70_120mm_OSBG tosidig; Type: ENZV_S-UK01B_S70_120mm_OSBG tosidig; Type Id: 2906763
Cross-Section Definition - Cross-Section: Vertical
Structural - Structural Usage: Non-bearing; Structural: no
Identity Data - Workset: Workset1
ePset_LocationTool - Splitting: RESULT
Constraints - Location Line: Finish Face: Exterior; Base is Attached: no; Related to Mass: no; Room Bounding: yes; Top is Attached: no; Base Constraint: H01
ePset_Simplebim - Assembly Level: Leaf
ePset_SimplebimBasicQuantities - Thickness (Simplebim): 120 mm; Height (Simplebim): 800 mm
Name (Basic Wall:ENZV_S-UK01B_S70_120mm_OSBG tosidig:...) | Area, side, gross, AABB (Simplebim) (m2) | Volume, net (Simplebim) (m3) | Area, side, net, larger (Simplebim) (m2) = Area, side, gross, larger (Simplebim) (m2) = Area, largest surface, net (Simplebim) (m2) | Area, side, gross, average (Simplebim) (m2) = Area, side, net, average (Simplebim) (m2) | Area, side, net, smaller (Simplebim) (m2) = Area, side, gross, smaller (Simplebim) (m2) | Length (Simplebim) (mm)
3049646 | 10.22 | 1.22642 | 10.2202 | 10.2202 | 10.2201 | 12775
3049648 | 1.6296 | 0.195534 | 1.62948 | 1.62945 | 1.62943 | 2037
3049651 | 0.48 | 0.0575849 | 0.479878 | 0.479874 | 0.47987 | 600
3049649 | 6.2496 | 0.749957 | 6.24964 | 6.24964 | 6.24964 | 7812
3049650 | 0.4808 | 0.0576981 | 0.480818 | 0.480818 | 0.480818 | 601

# IfcWall: Basic Wall:ENZV_S-UK01_S70_95mm_OSBG ensidig, Basic Wall:ENZV_S-UK01_S70_95mm_OSBG ensidig:3026146
In: H01
Type - PredefinedType: STANDARD; Material: A246.Gips 12.5mm fiberarmert -QK5.31112 13 mm, OSB plate 12 mm, A242.Stender Lettmetall 95mm -PJ3.111002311 70 mm
Type - Other - Category: Walls; Family Name: Basic Wall
Type - Construction - Function: Interior; Width: 95 mm; Wrapping at Inserts: Do not wrap; CQMaxWallHeight: 6000 mm
Type - Graphics - Coarse Scale Fill Color: 0
Type - Identity Data - Type Name: ENZV_S-UK01_S70_95mm_OSBG ensidig; Workset: Wall Types
Type - Analytical Properties - Absorptance: 0.1; Roughness: 1
Type - Materials and Finishes - Structural Material: A242.Stender Lettmetall 95mm -PJ3.111002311
Type - Text - Veggtype S: ENZV_S-K01_S95_145mm_OSBG
Phasing - Phase Created: Fase 1 - Som bygget
Other - Type: ENZV_S-UK01_S70_95mm_OSBG ensidig; Family: Basic Wall; Family and Type: Basic Wall: ENZV_S-UK01_S70_95mm_OSBG ensidig; Type Id: 2906592
ePset_LocationTool - Splitting: RESULT
Cross-Section Definition - Cross-Section: Vertical
Structural - Structural Usage: Non-bearing; Structural: no
Pset_ReinforcementBarPitchOfWall - Reference: ENZV_S-UK01_S70_95mm_OSBG ensidig; sets with these values: 2
Identity Data - Workset: Workset1
Constraints - Location Line: Finish Face: Exterior; Base is Attached: no; Related to Mass: no; Room Bounding: yes; Top is Attached: no; Base Constraint: H01
Pset_WallCommon - Reference: ENZV_S-UK01_S70_95mm_OSBG ensidig; IsExternal: no; ExtendToStructure: no; LoadBearing: no
ePset_SimplebimBasicQuantities - Area, side, gross, AABB (Simplebim): 0.36921 m2; Area, side, gross, smaller (Simplebim): 0.165141 m2; Area, side, net, smaller (Simplebim): 0.165141 m2; Volume, net (Simplebim): 0.0253775 m3; Thickness (Simplebim): 95 mm; Length (Simplebim): 397 mm; Height (Simplebim): 930 mm; Area, largest surface, net (Simplebim): 0.369122 m2; Area, side, gross, larger (Simplebim): 0.369122 m2; Area, side, net, larger (Simplebim): 0.369122 m2; Area, side, net, average (Simplebim): 0.267132 m2; Area, side, gross, average (Simplebim): 0.267132 m2
ePset_Simplebim - Assembly Level: Leaf

# IfcWall: Basic Wall:Påforingsvegg mellombygget, Basic Wall:Påforingsvegg mellombygget:3046709
In: H01
Type - PredefinedType: STANDARD; Material: A246.Gips 12.5mm fiberarmert -QK5.31112 13 mm, OSB plate 12 mm, A242.Stender Lettmetall 95mm -PJ3.111002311 50 mm
Type - Other - Category: Walls; Family Name: Basic Wall
Type - Construction - Function: Interior; Width: 75 mm; Wrapping at Inserts: Do not wrap; CQMaxWallHeight: 6000 mm
Type - Graphics - Coarse Scale Fill Color: 0
Type - Identity Data - Type Name: Påforingsvegg mellombygget; Workset: Wall Types
Type - Analytical Properties - Absorptance: 0.1; Roughness: 1
Type - Materials and Finishes - Structural Material: A242.Stender Lettmetall 95mm -PJ3.111002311
Type - Text - Veggtype S: Påforingsvegg mellombygget
Phasing - Phase Created: Fase 1 - Som bygget
Constraints - Base is Attached: no; Related to Mass: no; Room Bounding: yes; Top is Attached: yes; Base Constraint: H01; Top Constraint: Up to level: H02; Location Line: Core Face: Interior
Cross-Section Definition - Cross-Section: Vertical
Structural - Structural Usage: Non-bearing; Structural: no
ePset_SimplebimBasicQuantities - Area, side, net, average (Simplebim): 98.5013 m2; Area, side, gross, average (Simplebim): 98.5013 m2; Volume, net (Simplebim): 7.3876 m3; Area, side, gross, smaller (Simplebim): 98.4255 m2; Area, side, net, smaller (Simplebim): 98.4255 m2; Thickness (Simplebim): 75 mm; Height (Simplebim): 3500 mm; Length (Simplebim): 28771 mm; Area, side, gross, AABB (Simplebim): 100.698 m2; Area, largest surface, net (Simplebim): 98.577 m2; Area, side, gross, larger (Simplebim): 98.577 m2; Area, side, net, larger (Simplebim): 98.577 m2
Pset_QuantityTakeOff - Reference: Påforingsvegg mellombygget; sets with these values: 2
ePset_LocationTool - Splitting: RESULT
Other - Type Id: 2906559; Family: Basic Wall; Family and Type: Basic Wall: Påforingsvegg mellombygget; Type: Påforingsvegg mellombygget
Identity Data - Workset: Workset1
ePset_Simplebim - Assembly Level: Leaf
Pset_WallCommon - IsExternal: no; ExtendToStructure: yes; LoadBearing: no; Reference: Påforingsvegg mellombygget

# IfcWall: Basic Wall:Skjørt mellombygg (5)
In: H01
Type - PredefinedType: STANDARD; Material: A246.Gips 12.5mm fiberarmert -QK5.31112 12 mm, Stender/Isolasjon 98 mm
Type - Other - Category: Walls; Family Name: Basic Wall
Type - Construction - Function: Interior; Width: 110 mm; Wrapping at Inserts: Do not wrap; CQMaxWallHeight: 6000 mm
Type - Graphics - Coarse Scale Fill Color: 0
Type - Identity Data - Type Name: Skjørt mellombygg; Workset: Wall Types
Type - Analytical Properties - Absorptance: 0.1; Roughness: 1
Type - Materials and Finishes - Structural Material: Stender/Isolasjon
Type - Text - Veggtype S: Skjørt mellombygg ENZV_S-UK01_T98_110mm_G ENZV_S-UK10_T98_110mm_G
Phasing - Phase Created: Fase 1 - Som bygget
ePset_SimplebimBasicQuantities - Thickness (Simplebim): 110 mm
Cross-Section Definition - Cross-Section: Vertical
Structural - Structural Usage: Non-bearing; Structural: no
Other - Family: Basic Wall; Type Id: 2906411; Type: Skjørt mellombygg; Family and Type: Basic Wall: Skjørt mellombygg
ePset_LocationTool - Splitting: RESULT
Pset_WallCommon - IsExternal: no; ExtendToStructure: no; LoadBearing: no; Reference: Skjørt mellombygg
Identity Data - Workset: Workset1
Constraints - Location Line: Finish Face: Exterior; Base is Attached: no; Related to Mass: no; Room Bounding: yes; Top is Attached: no; Base Constraint: H01
ePset_Simplebim - Assembly Level: Leaf
Pset_ReinforcementBarPitchOfWall - Reference: Skjørt mellombygg; sets with these values: 2
Name (Basic Wall:Skjørt mellombygg:...) | Area, side, gross, AABB (Simplebim) (m2) | Volume, net (Simplebim) (m3) | Height (Simplebim) (mm) | Length (Simplebim) (mm) | Area, largest surface, net (Simplebim) (m2) = Area, side, gross, larger (Simplebim) (m2) = Area, side, net, larger (Simplebim) (m2) | Area, side, net, average (Simplebim) (m2) = Area, side, gross, average (Simplebim) (m2) | Area, side, gross, smaller (Simplebim) (m2) = Area, side, net, smaller (Simplebim) (m2)
3023934 | 6.436 | 0.707932 | 800 | 8045 | 6.43575 | 6.43575 | 6.43575
3048990 | 0.731024 | 0.0770486 | 976 | 749 | 0.731434 | 0.70044 | 0.669446
3026147 | 1.3432 | 0.147724 | 800 | 1679 | 1.34295 | 1.34295 | 1.34294
3048971 | 16.5288 | 1.81814 | 800 | 20661 | 16.5285 | 16.5285 | 16.5285
3049647 | 0.4808 | 0.0528888 | 800 | 601 | 0.480807 | 0.480807 | 0.480807

# IfcWall: Basic Wall:Standard - 150mm (3)
In: H01
Type - PredefinedType: STANDARD; Material: Vegg 150 mm
Type - Other - Category: Walls; Family Name: Basic Wall
Type - Construction - Function: Exterior; Width: 150 mm; Wrapping at Inserts: Do not wrap
Type - Graphics - Coarse Scale Fill Color: 12632256; Coarse Scale Fill Pattern: <Solid fill>
Type - Identity Data - Type Name: Standard - 150mm; Workset: Wall Types
Type - Analytical Properties - Absorptance: 0.1; Roughness: 1
Phasing - Phase Created: Fase 1 - Som bygget
Constraints - Base is Attached: no; Related to Mass: no; Room Bounding: yes; Base Constraint: H01; Top Constraint: Up to level: H02; Location Line: Core Face: Interior
Cross-Section Definition - Cross-Section: Vertical
Structural - Structural Usage: Non-bearing; Structural: no
Identity Data - Workset: Workset1
Other - Family: Basic Wall; Family and Type: Basic Wall: Standard - 150mm; Type Id: 129062; Type: Standard - 150mm
Pset_QuantityTakeOff - Reference: Standard - 150mm; sets with these values: 2
ePset_LocationTool - Splitting: RESULT
ePset_Simplebim - Assembly Level: Leaf
Pset_WallCommon - IsExternal: yes; LoadBearing: no; Reference: Standard - 150mm
Name (Basic Wall:Standard - 150mm:...) | Top is Attached = ExtendToStructure | Area, largest surface, net (Simplebim) (m2) | Volume, net (Simplebim) (m3) | Area, side, gross, smaller (Simplebim) (m2) | Area, side, gross, larger (Simplebim) (m2) | Area, side, net, smaller (Simplebim) (m2) | Area, side, gross, average (Simplebim) (m2) | Area, side, net, larger (Simplebim) (m2) | Area, side, net, average (Simplebim) (m2) | Thickness (Simplebim) (mm) | Height (Simplebim) (mm) | Length (Simplebim) (mm) | Area, side, gross, AABB (Simplebim) (m2)
3018173 | yes | 1.54562 | 0.163069 | Dimensions - Keep Concentric: yes; Graphics - Center Mark Visible: no
3046711 | no | 98.218 | 14.6658 | 99.0462 | 99.9392 | 97.325 | 99.4927 | 98.218 | 97.7715 | 150 | 3500 | 28067 | 98.2345
3046747 | yes | 0.664386 | 0.0996578 | 0.664383 | 0.664386 | 0.664383 | 0.664385 | 0.664386 | 0.664385 | 150 | 430 | 1545 | 0.66435

# IfcWall: Basic Wall:Standard - 220mm, Basic Wall:Standard - 220mm:3027669
In: H01
Type - PredefinedType: STANDARD; Material: Vegg 220 mm
Type - Other - Category: Walls; Family Name: Basic Wall
Type - Construction - Function: Exterior; Width: 220 mm; Wrapping at Inserts: Do not wrap
Type - Graphics - Coarse Scale Fill Color: 12632256; Coarse Scale Fill Pattern: <Solid fill>
Type - Identity Data - Type Name: Standard - 220mm; Workset: Wall Types
Type - Analytical Properties - Absorptance: 0.1; Roughness: 1
ePset_LocationTool - Splitting: RESULT
Phasing - Phase Created: Fase 1 - Som bygget
Constraints - Base is Attached: no; Related to Mass: no; Room Bounding: yes; Top is Attached: no; Base Constraint: H01; Location Line: Core Face: Interior
Cross-Section Definition - Cross-Section: Vertical
Structural - Structural Usage: Non-bearing; Structural: no
Identity Data - Workset: Workset1
Pset_WallCommon - IsExternal: yes; ExtendToStructure: no; LoadBearing: no; Reference: Standard - 220mm
ePset_SimplebimBasicQuantities - Area, side, gross, AABB (Simplebim): 2.668 m2; Thickness (Simplebim): 220 mm; Length (Simplebim): 667 mm; Height (Simplebim): 4000 mm; Area, side, gross, larger (Simplebim): 2.49205 m2; Area, side, net, larger (Simplebim): 2.49205 m2; Area, largest surface, net (Simplebim): 2.49205 m2; Area, side, gross, smaller (Simplebim): 1.17546 m2; Area, side, net, smaller (Simplebim): 1.17546 m2; Volume, net (Simplebim): 0.368015 m3; Area, side, net, average (Simplebim): 1.83376 m2; Area, side, gross, average (Simplebim): 1.83376 m2
Other - Type Id: 387035; Family: Basic Wall; Family and Type: Basic Wall: Standard - 220mm; Type: Standard - 220mm
ePset_Simplebim - Assembly Level: Leaf
Pset_QuantityTakeOff - Reference: Standard - 220mm; sets with these values: 2

# IfcWallStandardCase: Basic Wall:ENZV_IV-UK01_S70_120mm_OSBG, Basic Wall:ENZV_IV-UK01_S70_120mm_OSBG:3046716
In: H01
Type - PredefinedType: STANDARD; Material: A246.Gips 12.5mm fiberarmert -QK5.31112 13 mm, OSB plate 12 mm, A242.Stender Lettmetall 95mm -PJ3.111002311 70 mm, OSB plate 12 mm, A246.Gips 12.5mm fiberarmert -QK5.31112 13 mm
Type - Other - Category: Walls; Family Name: Basic Wall
Type - Construction - Function: Interior; Width: 120 mm; Wrapping at Inserts: Do not wrap; CQMaxWallHeight: 6000 mm
Type - Graphics - Coarse Scale Fill Color: 0
Type - Identity Data - Type Name: ENZV_IV-UK01_S70_120mm_OSBG; Workset: Wall Types; Type Mark: IV-UK01; Keynote: NB! Forsterket stender, c/c 450mm
Type - Analytical Properties - Absorptance: 0.1; Roughness: 1
Type - Materials and Finishes - Structural Material: A242.Stender Lettmetall 95mm -PJ3.111002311
Type - Text - Veggtype S: ENZV_IV-UK01_S70_120mm_OSBG
Phasing - Phase Created: Fase 1 - Som bygget
ePset_LocationTool - Splitting: ORIGINAL
Other - Family and Type: Basic Wall: ENZV_IV-UK01_S70_120mm_OSBG; Family: Basic Wall; Type: ENZV_IV-UK01_S70_120mm_OSBG; Type Id: 388080
Dimensions - Area: 6.5826 m2; Volume: 0.744085 m3; Length: 1867.26 mm
Cross-Section Definition - Cross-Section: Vertical
Structural - Structural Usage: Non-bearing; Structural: no
Identity Data - Workset: Workset1
Constraints - Top Offset: -525 mm; Base Extension Distance: 0 mm; Base is Attached: no; Base Offset: 0 mm; Related to Mass: no; Room Bounding: yes; Top Extension Distance: 0 mm; Top is Attached: no; Base Constraint: H01; Unconnected Height: 3675 mm; Top Constraint: Up to level: H02; Location Line: Core Face: Interior
ePset_SimplebimBasicQuantities - Area, side, net, larger (Simplebim): 6.5826 m2; Area, side, gross, larger (Simplebim): 6.5826 m2; Area, largest surface, net (Simplebim): 6.5826 m2; Area, side, gross, AABB (Simplebim): 6.5826 m2; Length (Simplebim): 1791.18 mm; Volume, net (Simplebim): 0.744085 m3; Thickness (Simplebim): 120 mm; Height (Simplebim): 3675 mm; Area, side, gross, smaller (Simplebim): 5.81882 m2; Area, side, net, smaller (Simplebim): 5.81882 m2; Area, side, net, average (Simplebim): 6.20071 m2; Area, side, gross, average (Simplebim): 6.20071 m2
Pset_QuantityTakeOff - Reference: ENZV_IV-UK01_S70_120mm_OSBG; sets with these values: 2
ePset_Simplebim - Assembly Level: Leaf
Pset_WallCommon - IsExternal: no; ExtendToStructure: no; LoadBearing: no; Reference: ENZV_IV-UK01_S70_120mm_OSBG
BaseQuantities - GrossFootprintArea: 0.202472 m2; GrossVolume: 0.789912 m3; GrossSideArea: 6.5826 m2; NetSideArea: 6.5826 m2; Length: 1791.18 mm; NetVolume: 0.744085 m3; Width: 120 mm; Height: 3675 mm

# IfcWallStandardCase: Basic Wall:ENZV_IV-UK02_S95_145mm_OSBG (2)
In: H01
Type - PredefinedType: STANDARD; Material: A246.Gips 12.5mm fiberarmert -QK5.31112 13 mm, OSB plate 12 mm, A242.Stender Lettmetall 95mm -PJ3.111002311 95 mm, OSB plate 12 mm, A246.Gips 12.5mm fiberarmert -QK5.31112 13 mm
Type - Other - Category: Walls; Family Name: Basic Wall
Type - Construction - Function: Interior; Width: 145 mm; Wrapping at Inserts: Do not wrap; CQMaxWallHeight: 6000 mm
Type - Graphics - Coarse Scale Fill Color: 0
Type - Identity Data - Type Name: ENZV_IV-UK02_S95_145mm_OSBG; Workset: Wall Types; Type Mark: IV-UK02
Type - Analytical Properties - Absorptance: 0.1; Roughness: 1
Type - Materials and Finishes - Structural Material: A242.Stender Lettmetall 95mm -PJ3.111002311
Type - Text - Veggtype S: ENZV_IV-UK02_S95_145mm_OSBG
Phasing - Phase Created: Fase 1 - Som bygget
ePset_SimplebimBasicQuantities - Thickness (Simplebim): 145 mm
Pset_QuantityTakeOff - Reference: ENZV_IV-UK02_S95_145mm_OSBG; sets with these values: 2
Cross-Section Definition - Cross-Section: Vertical
Constraints - Location Line: Finish Face: Exterior; Base Extension Distance: 0 mm; Base is Attached: no; Base Offset: 0 mm; Related to Mass: no; Room Bounding: yes; Top Extension Distance: 0 mm; Top is Attached: no; Top Offset: 0 mm; Base Constraint: H01
Structural - Structural Usage: Non-bearing; Structural: no
Identity Data - Workset: Workset1
Pset_WallCommon - Reference: ENZV_IV-UK02_S95_145mm_OSBG; IsExternal: no; ExtendToStructure: no; LoadBearing: no
Other - Type Id: 388076; Type: ENZV_IV-UK02_S95_145mm_OSBG; Family: Basic Wall; Family and Type: Basic Wall: ENZV_IV-UK02_S95_145mm_OSBG
ePset_LocationTool - Splitting: ORIGINAL
ePset_Simplebim - Assembly Level: Leaf
BaseQuantities - Width: 145 mm
Name (Basic Wall:ENZV_IV-UK02_S95_145mm_OSBG:...) | Length (Simplebim) (mm) = BaseQuantities, Length (mm) | Area, side, gross, larger (Simplebim) (m2) = Area, side, gross, AABB (Simplebim) (m2) | Area, side, net, larger (Simplebim) (m2) = Area, largest surface, net (Simplebim) (m2) = Area (m2) = NetSideArea (m2) = GrossSideArea (m2) | Area, side, gross, average (Simplebim) (m2) | Area, side, net, average (Simplebim) (m2) | Area, side, gross, smaller (Simplebim) (m2) | Area, side, net, smaller (Simplebim) (m2) | Height (Simplebim) (mm) = Unconnected Height (mm) = Height (mm) | Volume, net (Simplebim) (m3) = Volume (m3) = NetVolume (m3) | Dimensions, Length (mm) | GrossFootprintArea (m2) | GrossVolume (m3)
3048923 | 2111.91 | 7.76336 | 7.76336 | 7.60949 | 7.60949 | 7.45563 | 7.45563 | 3676 | 1.10338 | 2046.33 | 0.300157 | 1.12569
3048924 | 5798.87 | 15.6569 | 13.3148 | 15.5439 | 13.2018 | 15.4309 | 13.0888 | 2700 | 1.91426 | 5768.22 | 0.834766 | 1.93065

# IfcWallStandardCase: Basic Wall:ENZV_S-UK01_S70_95mm_OSBG ensidig (2)
In: H01
Type - PredefinedType: STANDARD; Material: A246.Gips 12.5mm fiberarmert -QK5.31112 13 mm, OSB plate 12 mm, A242.Stender Lettmetall 95mm -PJ3.111002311 70 mm
Type - Other - Category: Walls; Family Name: Basic Wall
Type - Construction - Function: Interior; Width: 95 mm; Wrapping at Inserts: Do not wrap; CQMaxWallHeight: 6000 mm
Type - Graphics - Coarse Scale Fill Color: 0
Type - Identity Data - Type Name: ENZV_S-UK01_S70_95mm_OSBG ensidig; Workset: Wall Types
Type - Analytical Properties - Absorptance: 0.1; Roughness: 1
Type - Materials and Finishes - Structural Material: A242.Stender Lettmetall 95mm -PJ3.111002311
Type - Text - Veggtype S: ENZV_S-K01_S95_145mm_OSBG
Phasing - Phase Created: Fase 1 - Som bygget
Other - Type: ENZV_S-UK01_S70_95mm_OSBG ensidig; Family: Basic Wall; Family and Type: Basic Wall: ENZV_S-UK01_S70_95mm_OSBG ensidig; Type Id: 2906592
ePset_SimplebimBasicQuantities - Thickness (Simplebim): 95 mm
ePset_LocationTool - Splitting: ORIGINAL
Constraints - Location Line: Finish Face: Exterior; Base Extension Distance: 0 mm; Base is Attached: no; Related to Mass: no; Room Bounding: yes; Top Extension Distance: 0 mm; Top is Attached: no; Top Offset: 0 mm; Base Constraint: H01; Base Offset: 2700 mm
Cross-Section Definition - Cross-Section: Vertical
Structural - Structural Usage: Non-bearing; Structural: no
Pset_ReinforcementBarPitchOfWall - Reference: ENZV_S-UK01_S70_95mm_OSBG ensidig; sets with these values: 2
Identity Data - Workset: Workset1
Pset_WallCommon - Reference: ENZV_S-UK01_S70_95mm_OSBG ensidig; IsExternal: no; ExtendToStructure: no; LoadBearing: no
ePset_Simplebim - Assembly Level: Leaf
BaseQuantities - Width: 95 mm
Name (Basic Wall:ENZV_S-UK01_S70_95mm_OSBG ensidig:...) | Length (Simplebim) (mm) = BaseQuantities, Length (mm) | Area, side, gross, AABB (Simplebim) (m2) = Area, side, gross, larger (Simplebim) (m2) = Area, side, net, larger (Simplebim) (m2) = Area, largest surface, net (Simplebim) (m2) = Area (m2) = GrossSideArea (m2) = NetSideArea (m2) | Volume, net (Simplebim) (m3) = Volume (m3) = NetVolume (m3) | Area, side, gross, average (Simplebim) (m2) = Area, side, net, average (Simplebim) (m2) | Height (Simplebim) (mm) = Unconnected Height (mm) = Height (mm) | Area, side, net, smaller (Simplebim) (m2) = Area, side, gross, smaller (Simplebim) (m2) | Dimensions, Length (mm) | GrossVolume (m3) | GrossFootprintArea (m2)
3045074 | 1591.73 | 1.55352 | 0.145045 | 1.52679 | 976 | 1.50006 | 1509.51 | 0.147585 | 0.148612
3045075 | 1894.08 | 1.76149 | 0.164919 | 1.73599 | 930 | 1.71048 | 1797.37 | 0.167342 | 0.177332

# IfcWallStandardCase: Basic Wall:Skjørt mellombygg, Basic Wall:Skjørt mellombygg:3045090
In: H01
Type - PredefinedType: STANDARD; Material: A246.Gips 12.5mm fiberarmert -QK5.31112 12 mm, Stender/Isolasjon 98 mm
Type - Other - Category: Walls; Family Name: Basic Wall
Type - Construction - Function: Interior; Width: 110 mm; Wrapping at Inserts: Do not wrap; CQMaxWallHeight: 6000 mm
Type - Graphics - Coarse Scale Fill Color: 0
Type - Identity Data - Type Name: Skjørt mellombygg; Workset: Wall Types
Type - Analytical Properties - Absorptance: 0.1; Roughness: 1
Type - Materials and Finishes - Structural Material: Stender/Isolasjon
Type - Text - Veggtype S: Skjørt mellombygg ENZV_S-UK01_T98_110mm_G ENZV_S-UK10_T98_110mm_G
Phasing - Phase Created: Fase 1 - Som bygget
Constraints - Location Line: Finish Face: Exterior; Base Extension Distance: 0 mm; Base is Attached: no; Related to Mass: no; Room Bounding: yes; Top Extension Distance: 0 mm; Top is Attached: no; Top Offset: 0 mm; Base Constraint: H01; Unconnected Height: 976 mm; Base Offset: 2700 mm
Cross-Section Definition - Cross-Section: Vertical
Structural - Structural Usage: Non-bearing; Structural: no
Other - Family: Basic Wall; Type Id: 2906411; Type: Skjørt mellombygg; Family and Type: Basic Wall: Skjørt mellombygg
Pset_WallCommon - IsExternal: no; ExtendToStructure: no; LoadBearing: no; Reference: Skjørt mellombygg
ePset_LocationTool - Splitting: ORIGINAL
ePset_SimplebimBasicQuantities - Area, side, net, smaller (Simplebim): 27.1283 m2; Area, side, gross, smaller (Simplebim): 27.1283 m2; Volume, net (Simplebim): 2.98753 m3; Area, side, gross, average (Simplebim): 27.1594 m2; Area, side, net, average (Simplebim): 27.1594 m2; Length (Simplebim): 27859 mm; Area, side, gross, AABB (Simplebim): 27.1904 m2; Area, largest surface, net (Simplebim): 27.1904 m2; Area, side, gross, larger (Simplebim): 27.1904 m2; Area, side, net, larger (Simplebim): 27.1904 m2; Thickness (Simplebim): 110 mm; Height (Simplebim): 976 mm
Identity Data - Workset: Workset1
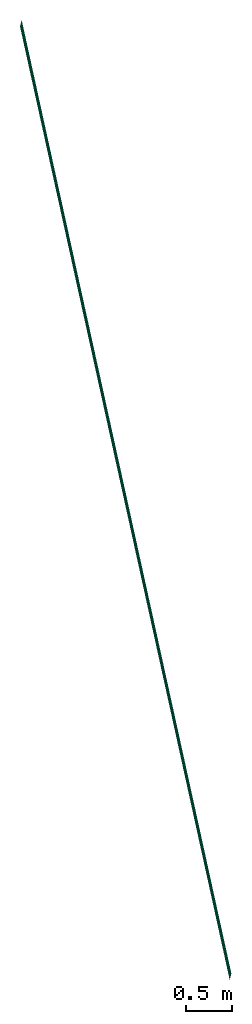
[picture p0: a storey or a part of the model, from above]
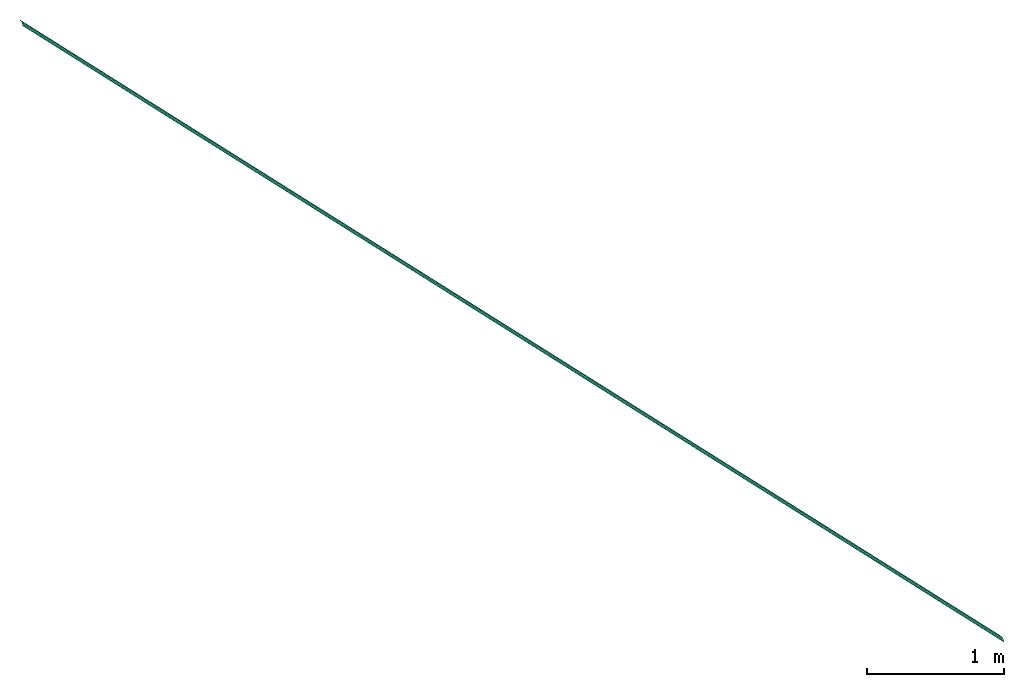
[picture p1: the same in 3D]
Properties of the parts of a building model (IFC2X3), part 2 of 2

# IfcWallStandardCase: Basic Wall:Skjørt mellombygg, Basic Wall:Skjørt mellombygg:3045090
Dimensions - Length: 27911 mm; Volume: 2.98753 m3; Area: 27.1904 m2
ePset_Simplebim - Assembly Level: Leaf
Pset_ReinforcementBarPitchOfWall - Reference: Skjørt mellombygg; sets with these values: 2
BaseQuantities - GrossFootprintArea: 3.06099 m2; NetVolume: 2.98753 m3; Length: 27859 mm; NetSideArea: 27.1904 m2; GrossSideArea: 27.1904 m2; Width: 110 mm; Height: 976 mm; GrossVolume: 2.99094 m3

# IfcWallStandardCase: Basic Wall:Standard - 100mm hvit, Basic Wall:Standard - 100mm hvit:3044845
In: H01
Type - PredefinedType: STANDARD; Material: Hvit 100 mm
Type - Other - Category: Walls; Family Name: Basic Wall
Type - Construction - Function: Exterior; Width: 100 mm; Wrapping at Inserts: Do not wrap
Type - Graphics - Coarse Scale Fill Color: 12632256; Coarse Scale Fill Pattern: <Solid fill>
Type - Identity Data - Type Name: Standard - 100mm hvit; Workset: Wall Types
Type - Analytical Properties - Absorptance: 0.1; Roughness: 1
Type - Materials and Finishes - Structural Material: Hvit
Phasing - Phase Created: Fase 1 - Som bygget
Constraints - Base Extension Distance: 0 mm; Base is Attached: no; Base Offset: 0 mm; Related to Mass: no; Room Bounding: yes; Top Extension Distance: 0 mm; Top is Attached: no; Top Offset: 0 mm; Base Constraint: H01; Unconnected Height: 2700 mm; Location Line: Core Face: Interior
Cross-Section Definition - Cross-Section: Vertical
Structural - Structural Usage: Non-bearing; Structural: no
ePset_LocationTool - Splitting: ORIGINAL
Pset_WallCommon - Reference: Standard - 100mm hvit; IsExternal: yes; ExtendToStructure: no; LoadBearing: no
Other - Type: Standard - 100mm hvit; Family: Basic Wall; Family and Type: Basic Wall: Standard - 100mm hvit; Type Id: 385312
Identity Data - Workset: Workset1
Dimensions - Length: 12319 mm; Area: 30.7741 m2; Volume: 3.07741 m3
Pset_ReinforcementBarPitchOfWall - Reference: Standard - 100mm hvit; sets with these values: 2
ePset_Simplebim - Assembly Level: Leaf
ePset_SimplebimBasicQuantities - Length (Simplebim): 12319 mm; Area, side, gross, AABB (Simplebim): 33.2613 m2; Area, side, gross, average (Simplebim): 33.2613 m2; Area, side, gross, larger (Simplebim): 33.2613 m2; Area, side, gross, smaller (Simplebim): 33.2613 m2; Area, side, net, smaller (Simplebim): 30.7741 m2; Area, side, net, larger (Simplebim): 30.7741 m2; Area, side, net, average (Simplebim): 30.7741 m2; Area, largest surface, net (Simplebim): 30.7741 m2; Volume, net (Simplebim): 3.07741 m3; Thickness (Simplebim): 100 mm; Height (Simplebim): 2700 mm
BaseQuantities - Length: 12319 mm; GrossSideArea: 30.7741 m2; NetSideArea: 30.7741 m2; GrossFootprintArea: 1.2319 m2; GrossVolume: 3.07741 m3; NetVolume: 3.07741 m3; Width: 100 mm; Height: 2700 mm

# IfcWallStandardCase: Basic Wall:Standard - 120mm, Basic Wall:Standard - 120mm:3046713
In: H01
Type - PredefinedType: STANDARD; Material: Vegg - Gips 120 mm
Type - Other - Category: Walls; Family Name: Basic Wall
Type - Construction - Function: Exterior; Width: 120 mm; Wrapping at Inserts: Do not wrap
Type - Graphics - Coarse Scale Fill Color: 12632256; Coarse Scale Fill Pattern: <Solid fill>
Type - Identity Data - Type Name: Standard - 120mm; Workset: Wall Types
Type - Analytical Properties - Absorptance: 0.1; Roughness: 1
Type - Materials and Finishes - Structural Material: Vegg - Gips
Phasing - Phase Created: Fase 1 - Som bygget
Other - Type Id: 386667; Family: Basic Wall; Family and Type: Basic Wall: Standard - 120mm; Type: Standard - 120mm
Cross-Section Definition - Cross-Section: Vertical
ePset_SimplebimBasicQuantities - Area, side, gross, smaller (Simplebim): 108.996 m2; Area, side, gross, average (Simplebim): 109.022 m2; Area, side, gross, larger (Simplebim): 109.047 m2; Volume, net (Simplebim): 12.3226 m3; Area, side, net, larger (Simplebim): 102.644 m2; Area, largest surface, net (Simplebim): 102.644 m2; Length (Simplebim): 28574.6 mm; Thickness (Simplebim): 120 mm; Height (Simplebim): 3676 mm; Area, side, gross, AABB (Simplebim): 105.04 m2; Area, side, net, smaller (Simplebim): 102.593 m2; Area, side, net, average (Simplebim): 102.618 m2
Structural - Structural Usage: Non-bearing; Structural: no
ePset_LocationTool - Splitting: ORIGINAL
Identity Data - Workset: Workset1
Pset_ReinforcementBarPitchOfWall - Reference: Standard - 120mm; sets with these values: 2
ePset_Simplebim - Assembly Level: Leaf
Dimensions - Length: 28667 mm; Volume: 12.3254 m3; Area: 102.644 m2
Pset_WallCommon - IsExternal: yes; ExtendToStructure: no; LoadBearing: no; Reference: Standard - 120mm
Constraints - Unconnected Height: 3676 mm; Base Extension Distance: 0 mm; Base is Attached: no; Base Offset: 0 mm; Related to Mass: no; Room Bounding: yes; Top Extension Distance: 0 mm; Top is Attached: no; Top Offset: 0 mm; Base Constraint: H01; Location Line: Core Face: Interior
BaseQuantities - GrossFootprintArea: 3.4248 m2; GrossVolume: 12.3172 m3; NetVolume: 12.3254 m3; Length: 28574.6 mm; Width: 120 mm; Height: 3676 mm; GrossSideArea: 102.644 m2; NetSideArea: 102.644 m2
